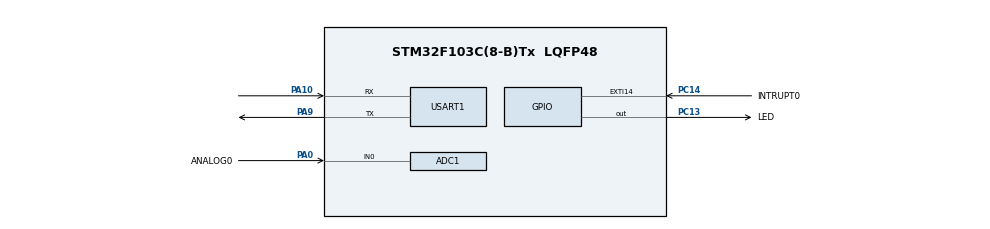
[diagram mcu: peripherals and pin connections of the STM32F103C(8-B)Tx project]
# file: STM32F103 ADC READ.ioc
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ADC1.Channel-0\#ChannelRegularConversion=ADC_CHANNEL_0
ADC1.NbrOfConversionFlag=1
ADC1.Rank-0\#ChannelRegularConversion=1
ADC1.SamplingTime-0\#ChannelRegularConversion=ADC_SAMPLETIME_1CYCLE_5
ADC1.master=1
Dma.ADC1.0.Direction=DMA_PERIPH_TO_MEMORY
Dma.ADC1.0.Instance=DMA1_Channel1
Dma.ADC1.0.MemDataAlignment=DMA_MDATAALIGN_HALFWORD
Dma.ADC1.0.MemInc=DMA_MINC_ENABLE
Dma.ADC1.0.Mode=DMA_CIRCULAR
Dma.ADC1.0.PeriphDataAlignment=DMA_PDATAALIGN_HALFWORD
Dma.ADC1.0.PeriphInc=DMA_PINC_DISABLE
Dma.ADC1.0.Priority=DMA_PRIORITY_LOW
Dma.Request0=ADC1
Dma.Request1=USART1_TX
Dma.USART1_TX.1.Direction=DMA_MEMORY_TO_PERIPH
Dma.USART1_TX.1.Instance=DMA1_Channel4
Dma.USART1_TX.1.MemDataAlignment=DMA_MDATAALIGN_BYTE
Dma.USART1_TX.1.MemInc=DMA_MINC_ENABLE
Dma.USART1_TX.1.Mode=DMA_NORMAL
Dma.USART1_TX.1.PeriphDataAlignment=DMA_PDATAALIGN_BYTE
Dma.USART1_TX.1.PeriphInc=DMA_PINC_DISABLE
Dma.USART1_TX.1.Priority=DMA_PRIORITY_LOW
Mcu.Family=STM32F1
Mcu.Name=STM32F103C(8-B)Tx
Mcu.Package=LQFP48
NVIC.DMA1_Channel1_IRQn=true\:0\:0\:false\:false\:true\:false\:true\:true
NVIC.DMA1_Channel4_IRQn=true\:0\:0\:false\:false\:true\:false\:true\:true
NVIC.EXTI15_10_IRQn=true\:0\:0\:false\:false\:true\:true\:true\:true
NVIC.PriorityGroup=NVIC_PRIORITYGROUP_4
NVIC.USART1_IRQn=true\:0\:0\:false\:false\:true\:true\:true\:true
PA0-WKUP.GPIO_Label=ANALOG0
PA0-WKUP.Signal=ADCx_IN0
PA10.Mode=Asynchronous
PA10.Signal=USART1_RX
PA13.Mode=Serial_Wire
PA13.Signal=SYS_JTMS-SWDIO
PA14.Mode=Serial_Wire
PA14.Signal=SYS_JTCK-SWCLK
PA9.Mode=Asynchronous
PA9.Signal=USART1_TX
PC13-TAMPER-RTC.GPIO_Label=LED
PC13-TAMPER-RTC.Signal=GPIO_Output
PC14-OSC32_IN.GPIO_Label=INTRUPT0
PC14-OSC32_IN.GPIO_ModeDefaultEXTI=GPIO_MODE_IT_FALLING
PC14-OSC32_IN.Signal=GPXTI14
ProjectManager.HeapSize=0x200
ProjectManager.StackSize=0x400
ProjectManager.TargetToolchain=STM32CubeIDE
RCC.ADCPresc=RCC_ADCPCLK2_DIV6
RCC.AHBFreq_Value=64000000
RCC.APB1CLKDivider=RCC_HCLK_DIV2
RCC.APB1Freq_Value=32000000
RCC.APB1TimFreq_Value=64000000
RCC.APB2Freq_Value=64000000
RCC.APB2TimFreq_Value=64000000
RCC.HCLKFreq_Value=64000000
RCC.PLLMUL=RCC_PLL_MUL16
RCC.SYSCLKFreq_VALUE=64000000
RCC.SYSCLKSource=RCC_SYSCLKSOURCE_PLLCLK
RCC.USBFreq_Value=64000000
SH.ADCx_IN0.0=ADC1_IN0,IN0
TIM1.Channel-Output\ Compare1\ No\ Output=TIM_CHANNEL_1
TIM1.Period=9999
TIM1.Prescaler=6399
USART1.VirtualMode=VM_ASYNC
VP_TIM1_VS_no_output1.Mode=Output Compare1 No Output
board=custom

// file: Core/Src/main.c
/* USER CODE BEGIN Header */
/**
  ******************************************************************************
  * @file           : main.c
  * @brief          : Main program body
  ******************************************************************************
  */
/* USER CODE END Header */
#include "main.h"
#include <string.h>
#include <stdio.h>

#define ADC_BUFFER_SIZE 100
#define UART_BUFFER_SIZE 50

ADC_HandleTypeDef hadc1;
DMA_HandleTypeDef hdma_adc1;
TIM_HandleTypeDef htim1;
UART_HandleTypeDef huart1;

/* USER CODE BEGIN PV */
volatile uint16_t adc_value;
volatile uint8_t ADC_Sample_Flag = 0;
volatile uint8_t RCA_Flag = 0;
char uart_buffer[UART_BUFFER_SIZE];
uint32_t adc[ADC_BUFFER_SIZE];
uint32_t Mean;
uint32_t sample_index = 0;
uint64_t Last_GetTick = 0;
/* USER CODE END PV */

void SystemClock_Config(void);
static void MX_GPIO_Init(void);
static void MX_DMA_Init(void);
static void MX_ADC1_Init(void);
static void MX_USART1_UART_Init(void);
static void MX_TIM1_Init(void);
void Error_Handler(void);

int main(void)
{
  HAL_Init();
  SystemClock_Config();
  MX_GPIO_Init();
  MX_DMA_Init();
  MX_ADC1_Init();
  MX_USART1_UART_Init();
  MX_TIM1_Init();

  /* USER CODE BEGIN 2 */
  HAL_TIM_Base_Start_IT(&htim1);
  HAL_ADC_Start_DMA(&hadc1, (uint32_t*)&adc_value, 1);
  /* USER CODE END 2 */

  /* Infinite loop */
  while (1)
  {
      if ((HAL_GetTick() - Last_GetTick >= 1000) && (ADC_Sample_Flag == 0) && (RCA_Flag == 1))
      {
          if (sample_index < ADC_BUFFER_SIZE)
          {
              adc[sample_index] = adc_value;
              sample_index++;
              Last_GetTick = HAL_GetTick();

              if (sample_index >= ADC_BUFFER_SIZE)
              {
                  ADC_Sample_Flag = 1;
                  RCA_Flag = 0;
              }
          }
      }

      if (ADC_Sample_Flag == 1)
      {
          uint64_t sum = 0;
          for (int j = 0; j < ADC_BUFFER_SIZE; j++)
          {
              sum += adc[j];
          }
          Mean = sum / ADC_BUFFER_SIZE;
          sprintf(uart_buffer, "Mean ADC: %lu\r\n", Mean);

          sample_index = 0;
          ADC_Sample_Flag = 0;
          RCA_Flag = 0;
      }

      HAL_Delay(1);
  }
}

void SystemClock_Config(void)
{
  RCC_OscInitTypeDef RCC_OscInitStruct = {0};
  RCC_ClkInitTypeDef RCC_ClkInitStruct = {0};

  RCC_OscInitStruct.OscillatorType = RCC_OSCILLATORTYPE_HSE;
  RCC_OscInitStruct.HSEState = RCC_HSE_ON;
  RCC_OscInitStruct.HSEPredivValue = RCC_HSE_PREDIV_DIV1;
  RCC_OscInitStruct.HSIState = RCC_HSI_ON;
  RCC_OscInitStruct.PLL.PLLState = RCC_PLL_ON;
  RCC_OscInitStruct.PLL.PLLSource = RCC_PLLSOURCE_HSE;
  RCC_OscInitStruct.PLL.PLLMUL = RCC_PLL_MUL9;
  if (HAL_RCC_OscConfig(&RCC_OscInitStruct) != HAL_OK)
  {
    Error_Handler();
  }

  RCC_ClkInitStruct.ClockType = RCC_CLOCKTYPE_HCLK | RCC_CLOCKTYPE_SYSCLK
                              | RCC_CLOCKTYPE_PCLK1 | RCC_CLOCKTYPE_PCLK2;
  RCC_ClkInitStruct.SYSCLKSource = RCC_SYSCLKSOURCE_PLLCLK;
  RCC_ClkInitStruct.AHBCLKDivider = RCC_SYSCLK_DIV1;
  RCC_ClkInitStruct.APB1CLKDivider = RCC_HCLK_DIV2;
  RCC_ClkInitStruct.APB2CLKDivider = RCC_HCLK_DIV1;

  if (HAL_RCC_ClockConfig(&RCC_ClkInitStruct, FLASH_LATENCY_2) != HAL_OK)
  {
    Error_Handler();
  }
}

static void MX_GPIO_Init(void)
{
  GPIO_InitTypeDef GPIO_InitStruct = {0};

  /* GPIO Ports Clock Enable */
  __HAL_RCC_GPIOC_CLK_ENABLE();
  __HAL_RCC_GPIOA_CLK_ENABLE();
  __HAL_RCC_GPIOB_CLK_ENABLE();

  /* Configure LED Pin (PC13) */
  GPIO_InitStruct.Pin = GPIO_PIN_13;
  GPIO_InitStruct.Mode = GPIO_MODE_OUTPUT_PP;
  GPIO_InitStruct.Pull = GPIO_NOPULL;
  GPIO_InitStruct.Speed = GPIO_SPEED_FREQ_LOW;
  HAL_GPIO_Init(GPIOC, &GPIO_InitStruct);

  /* Configure Interrupt Pin (PA0) */
  GPIO_InitStruct.Pin = GPIO_PIN_0;
  GPIO_InitStruct.Mode = GPIO_MODE_IT_FALLING;
  GPIO_InitStruct.Pull = GPIO_PULLUP;
  HAL_GPIO_Init(GPIOA, &GPIO_InitStruct);

  /* Configure ADC Pin (PA0 as analog) */
  GPIO_InitStruct.Pin = GPIO_PIN_0;
  GPIO_InitStruct.Mode = GPIO_MODE_ANALOG;
  HAL_GPIO_Init(GPIOA, &GPIO_InitStruct);

  /* Configure USART Pins (PA9 TX, PA10 RX) */
  GPIO_InitStruct.Pin = GPIO_PIN_9 | GPIO_PIN_10;
  GPIO_InitStruct.Mode = GPIO_MODE_AF_PP;
  GPIO_InitStruct.Speed = GPIO_SPEED_FREQ_HIGH;
  HAL_GPIO_Init(GPIOA, &GPIO_InitStruct);

  /* EXTI interrupt init*/
  HAL_NVIC_SetPriority(EXTI0_IRQn, 0, 0);
  HAL_NVIC_EnableIRQ(EXTI0_IRQn);
}

static void MX_DMA_Init(void)
{
  /* DMA controller clock enable */
  __HAL_RCC_DMA1_CLK_ENABLE();

  /* DMA interrupt init */
  HAL_NVIC_SetPriority(DMA1_Channel1_IRQn, 0, 0);
  HAL_NVIC_EnableIRQ(DMA1_Channel1_IRQn);
}

static void MX_ADC1_Init(void)
{
  ADC_ChannelConfTypeDef sConfig = {0};

  hadc1.Instance = ADC1;
  hadc1.Init.ScanConvMode = ADC_SCAN_DISABLE;
  hadc1.Init.ContinuousConvMode = ENABLE;  // Ubah ke ENABLE untuk continuous
  hadc1.Init.DiscontinuousConvMode = DISABLE;
  hadc1.Init.ExternalTrigConv = ADC_SOFTWARE_START;
  hadc1.Init.DataAlign = ADC_DATAALIGN_RIGHT;
  hadc1.Init.NbrOfConversion = 1;
  if (HAL_ADC_Init(&hadc1) != HAL_OK)
  {
    Error_Handler();
  }

  sConfig.Channel = ADC_CHANNEL_0;
  sConfig.Rank = ADC_REGULAR_RANK_1;
  sConfig.SamplingTime = ADC_SAMPLETIME_55CYCLES_5;
  if (HAL_ADC_ConfigChannel(&hadc1, &sConfig) != HAL_OK)
  {
    Error_Handler();
  }
}

static void MX_USART1_UART_Init(void)
{
  huart1.Instance = USART1;
  huart1.Init.BaudRate = 115200;
  huart1.Init.WordLength = UART_WORDLENGTH_8B;
  huart1.Init.StopBits = UART_STOPBITS_1;
  huart1.Init.Parity = UART_PARITY_NONE;
  huart1.Init.Mode = UART_MODE_TX_RX;
  huart1.Init.HwFlowCtl = UART_HWCONTROL_NONE;
  huart1.Init.OverSampling = UART_OVERSAMPLING_16;
  if (HAL_UART_Init(&huart1) != HAL_OK)
  {
    Error_Handler();
  }
}

static void MX_TIM1_Init(void)
{
  TIM_ClockConfigTypeDef sClockSourceConfig = {0};
  TIM_MasterConfigTypeDef sMasterConfig = {0};

  htim1.Instance = TIM1;
  htim1.Init.Prescaler = 7200 - 1;  // 72MHz / 7200 = 10kHz
  htim1.Init.CounterMode = TIM_COUNTERMODE_UP;
  htim1.Init.Period = 10000 - 1;    // 10kHz / 10000 = 1Hz (1 detik)
  htim1.Init.ClockDivision = TIM_CLOCKDIVISION_DIV1;
  htim1.Init.RepetitionCounter = 0;
  htim1.Init.AutoReloadPreload = TIM_AUTORELOAD_PRELOAD_ENABLE;
  if (HAL_TIM_Base_Init(&htim1) != HAL_OK)
  {
    Error_Handler();
  }

  sClockSourceConfig.ClockSource = TIM_CLOCKSOURCE_INTERNAL;
  if (HAL_TIM_ConfigClockSource(&htim1, &sClockSourceConfig) != HAL_OK)
  {
    Error_Handler();
  }

  sMasterConfig.MasterOutputTrigger = TIM_TRGO_RESET;
  sMasterConfig.MasterSlaveMode = TIM_MASTERSLAVEMODE_DISABLE;
  if (HAL_TIMEx_MasterConfigSynchronization(&htim1, &sMasterConfig) != HAL_OK)
  {
    Error_Handler();
  }
}

/* USER CODE BEGIN 4 */
void HAL_GPIO_EXTI_Callback(uint16_t GPIO_Pin)
{
    if(GPIO_Pin == GPIO_PIN_0)
    {
        RCA_Flag = 1;
        Last_GetTick = HAL_GetTick();
    }
}

void HAL_ADC_ConvCpltCallback(ADC_HandleTypeDef* hadc)
{
    if (hadc->Instance == ADC1)
    {
        // Data siap
    }
}

void HAL_TIM_PeriodElapsedCallback(TIM_HandleTypeDef *htim)
{
    if (htim->Instance == TIM1)
    {
        if (strlen(uart_buffer) > 0)
        {
            HAL_UART_Transmit(&huart1, (uint8_t*)uart_buffer, strlen(uart_buffer), 100);
            uart_buffer[0] = '\0';
        }
    }
}
/* USER CODE END 4 */

void Error_Handler(void)
{
  __disable_irq();
  while (1)
  {
  }
}
